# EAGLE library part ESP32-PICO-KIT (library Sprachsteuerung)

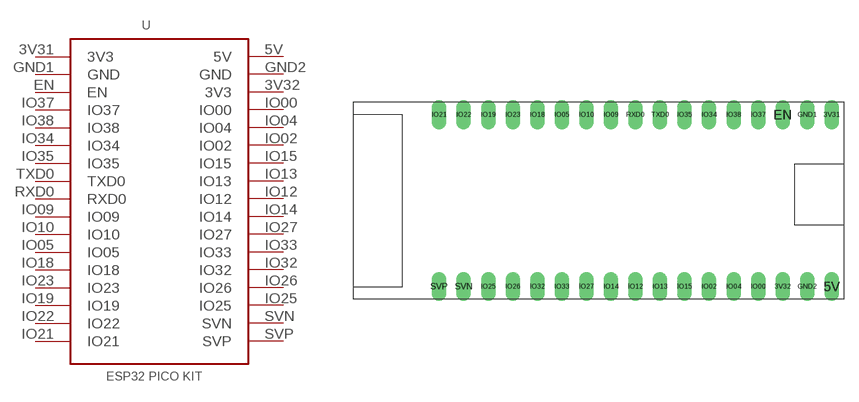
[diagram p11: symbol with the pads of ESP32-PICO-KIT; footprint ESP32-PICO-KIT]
Designator prefix -

## ESP32-PICO-KIT  [ESP32-PICO-KIT]
3V31  3V3  pwr
3V32  3V3  pwr
5V  5V  pwr
EN  EN
GND1  GND  pwr
GND2  GND  pwr
IO00  IO00
IO02  IO02
IO04  IO04
IO05  IO05
IO09  IO09
IO10  IO10
IO12  IO12
IO13  IO13
IO14  IO14
IO15  IO15
IO18  IO18
IO19  IO19
IO21  IO21
IO22  IO22
IO23  IO23
IO25  IO25
IO26  IO26
IO27  IO27
IO32  IO32
IO33  IO33
IO34  IO34
IO35  IO35
IO37  IO37
IO38  IO38
RXD0  RXD0
SVN  SVN
SVP  SVP
TXD0  TXD0

## Footprint ESP32-PICO-KIT (pad centres in mm)
drill 1 pad 1.422 long: 3V31 22.86,5.08; 3V32 17.78,-12.7; 5V 22.86,-12.7; EN 17.78,5.08; GND1 20.32,5.08; GND2 20.32,-12.7; IO00 15.24,-12.7; IO02 10.16,-12.7; IO04 12.7,-12.7; IO05 -5.08,5.08; IO09 0,5.08; IO10 -2.54,5.08; IO12 2.54,-12.7; IO13 5.08,-12.7; IO14 0,-12.7; IO15 7.62,-12.7; IO18 -7.62,5.08; IO19 -12.7,5.08; IO21 -17.78,5.08; IO22 -15.24,5.08; IO23 -10.16,5.08; IO25 -12.7,-12.7; IO26 -10.16,-12.7; IO27 -2.54,-12.7; IO32 -7.62,-12.7; IO33 -5.08,-12.7; IO34 10.16,5.08; IO35 7.62,5.08; IO37 15.24,5.08; IO38 12.7,5.08; RXD0 2.54,5.08; SVN -15.24,-12.7; SVP -17.78,-12.7; TXD0 5.08,5.08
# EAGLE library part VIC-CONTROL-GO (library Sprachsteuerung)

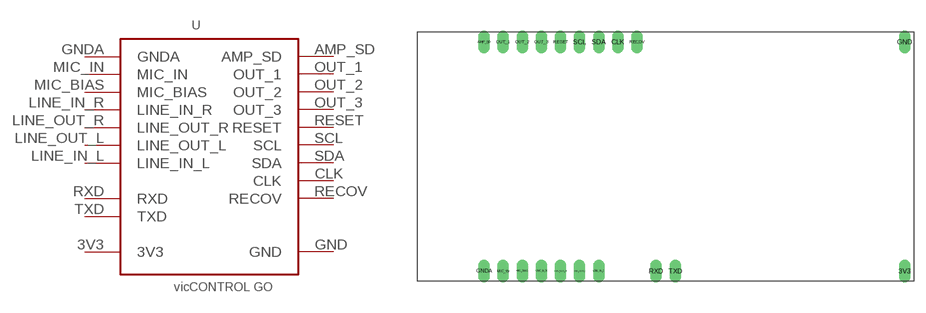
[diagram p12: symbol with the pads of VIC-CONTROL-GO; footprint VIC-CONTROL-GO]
Designator prefix -

## VIC-CONTROL-GO  [VIC-CONTROL-GO]
3V3  3V3  pwr
AMP_SD  AMP_SD
CLK  CLK
GND  GND  pwr
GNDA  GNDA  pwr
LINE_IN_L  LINE_IN_L
LINE_IN_R  LINE_IN_R
LINE_OUT_L  LINE_OUT_L
LINE_OUT_R  LINE_OUT_R
MIC_BIAS  MIC_BIAS
MIC_IN  MIC_IN
OUT_1  OUT_1
OUT_2  OUT_2
OUT_3  OUT_3
RECOV  RECOV
RESET  RESET
RXD  RXD
SCL  SCL
SDA  SDA
TXD  TXD

## Footprint VIC-CONTROL-GO (pad centres in mm)
drill 1 pad 1.422 long: 3V3 38.1,-12.7; AMP_SD -17.78,17.78; CLK 0,17.78; GND 38.1,17.78; GNDA -17.78,-12.7; LINE_IN_L -2.54,-12.7; LINE_IN_R -10.16,-12.7; LINE_OUT_L -5.08,-12.7; LINE_OUT_R -7.62,-12.7; MIC_BIAS -12.7,-12.7; MIC_IN -15.24,-12.7; OUT_1 -15.24,17.78; OUT_2 -12.7,17.78; OUT_3 -10.16,17.78; RECOV 2.54,17.78; RESET -7.62,17.78; RXD 5.08,-12.7; SCL -5.08,17.78; SDA -2.54,17.78; TXD 7.62,-12.7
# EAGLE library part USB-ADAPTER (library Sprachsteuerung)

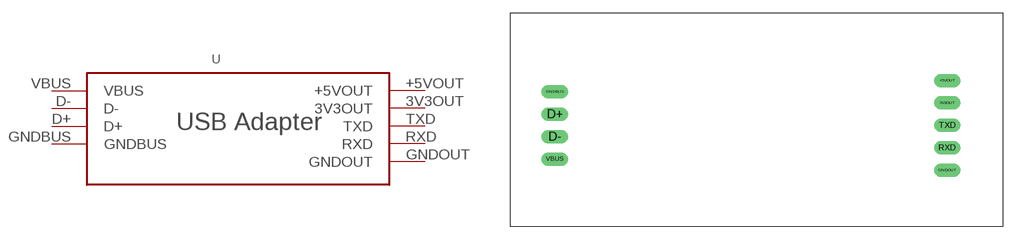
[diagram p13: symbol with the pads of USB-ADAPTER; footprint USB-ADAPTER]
Designator prefix -

## USB-ADAPTER  [USB-ADAPTER]
3V3OUT  3V3OUT  pwr
+5VOUT  +5VOUT  pwr
D+  D+
D-  D-
GNDBUS  GNDBUS  pwr
GNDOUT  GNDOUT  pwr
RXD  RXD
TXD  TXD
VBUS  VBUS  pwr

## Footprint USB-ADAPTER (pad centres in mm)
drill 1 pad 1.422 long: 3V3OUT 24.13,1.27; +5VOUT 24.13,3.81; D+ -20.32,0; D- -20.32,-2.54; GNDBUS -20.32,2.54; GNDOUT 24.13,-6.35; RXD 24.13,-3.81; TXD 24.13,-1.27; VBUS -20.32,-5.08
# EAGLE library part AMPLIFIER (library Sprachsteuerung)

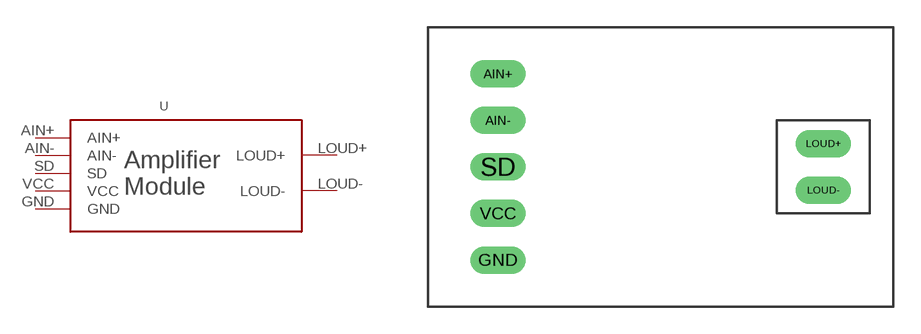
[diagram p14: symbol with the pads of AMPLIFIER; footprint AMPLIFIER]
Designator prefix -

## AMPLIFIER  [AMPLIFIER]
AIN+  AIN+
AIN-  AIN-
GND  GND  pwr
LOUD+  LOUD+
LOUD-  LOUD-
SD  SD
VCC  VCC  pwr

## Footprint AMPLIFIER (pad centres in mm)
drill 1 pad 1.422 long: AIN+ -20.32,2.54; AIN- -20.32,0; GND -20.32,-7.62; LOUD+ -2.54,-1.27; LOUD- -2.54,-3.81; SD -20.32,-2.54; VCC -20.32,-5.08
